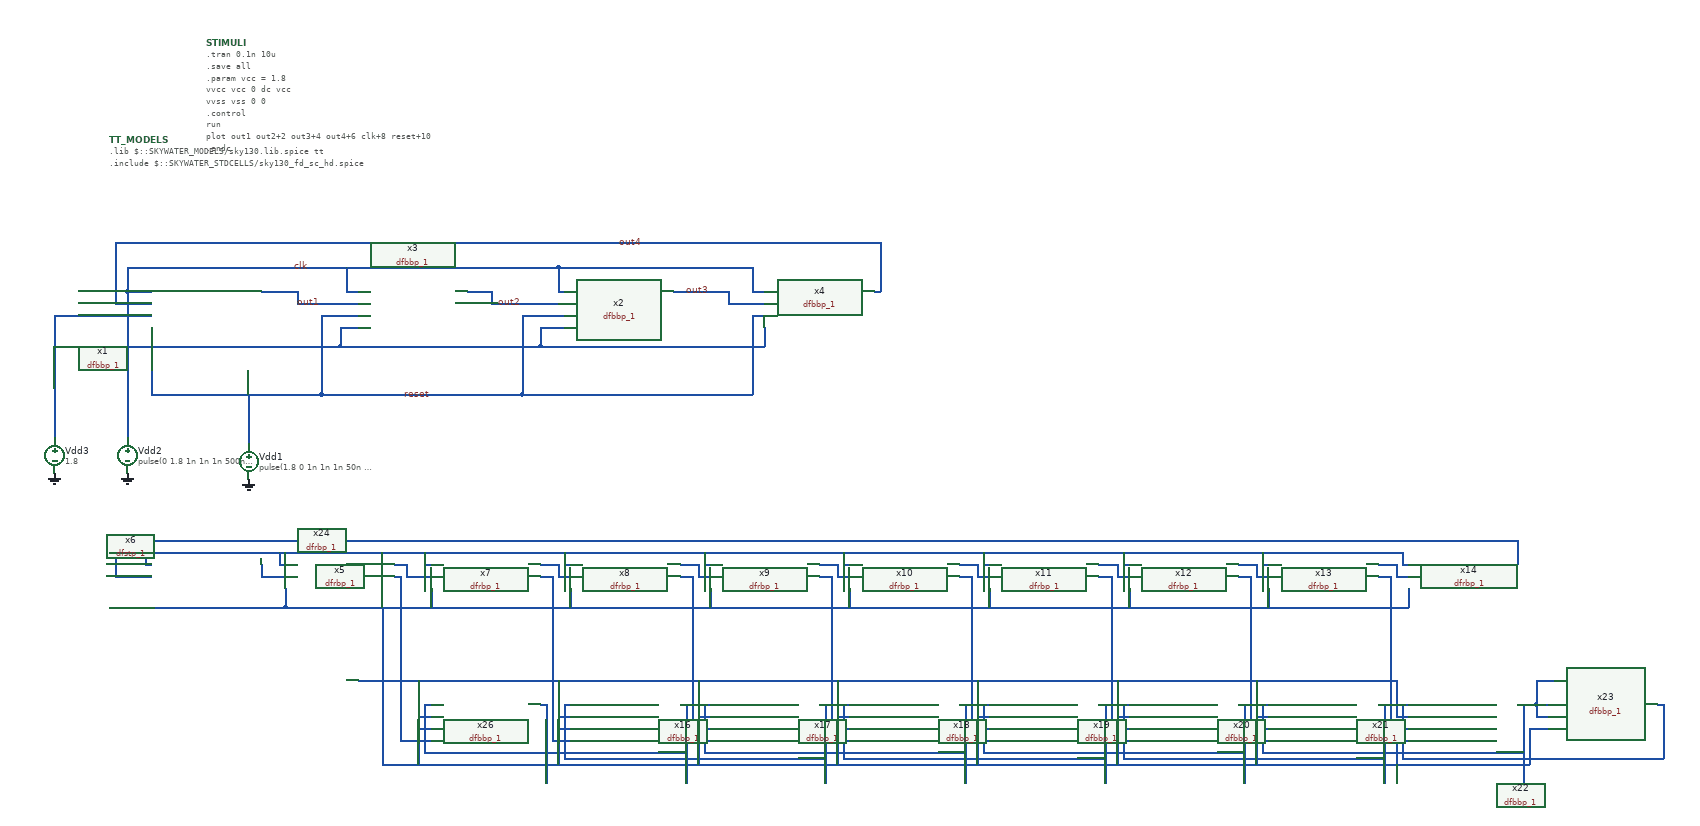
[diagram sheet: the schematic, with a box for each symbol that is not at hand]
v {xschem version=3.4.5 file_version=1.2
}
G {}
K {}
V {}
S {}
E {}
N -80 240 -80 270 {
lab=#net1}
N -80 240 80 240 {
lab=#net1}
N 260 200 320 200 {
lab=out1}
N 40 200 80 200 {
lab=clk}
N 320 200 320 220 {
lab=out1}
N 320 220 420 220 {
lab=out1}
N 600 200 640 200 {
lab=out2}
N 640 200 640 220 {
lab=out2}
N 640 220 760 220 {
lab=out2}
N 40 160 40 200 {
lab=clk}
N 60 160 750 160 {
lab=clk}
N 750 160 750 200 {
lab=clk}
N 750 200 760 200 {
lab=clk}
N 400 200 420 200 {
lab=clk}
N 400 160 400 200 {
lab=clk}
N -80 270 -80 360 {
lab=#net1}
N 390 240 420 240 {
lab=reset}
N 390 260 420 260 {
lab=#net1}
N 390 290 720 290 {
lab=#net1}
N 720 240 760 240 {
lab=reset}
N 720 260 760 260 {
lab=#net1}
N 20 120 940 120 {
lab=out4}
N 20 120 20 220 {
lab=out4}
N 40 160 60 160 {
lab=clk}
N -80 290 390 290 {
lab=#net1}
N 40 200 40 260 {
lab=clk}
N 20 220 80 220 {
lab=out4}
N 80 260 80 370 {
lab=reset}
N 650 220 750 220 {
lab=out2}
N 720 260 720 290 {
lab=#net1}
N 390 260 390 290 {
lab=#net1}
N 200 370 360 370 {
lab=reset}
N 360 240 360 370 {
lab=reset}
N 360 240 390 240 {
lab=reset}
N 360 370 690 370 {
lab=reset}
N 690 240 690 370 {
lab=reset}
N 690 240 720 240 {
lab=reset}
N 750 160 1070 160 {
lab=clk}
N 1070 160 1070 200 {
lab=clk}
N 1070 200 1090 200 {
lab=clk}
N 940 200 1030 200 {
lab=out3}
N 1030 200 1030 220 {
lab=out3}
N 1030 220 1090 220 {
lab=out3}
N 690 370 1070 370 {
lab=reset}
N 1070 240 1070 370 {
lab=reset}
N 1070 240 1090 240 {
lab=reset}
N 720 290 1090 290 {
lab=#net1}
N 1090 260 1090 290 {
lab=#net1}
N 940 120 1280 120 {
lab=out4}
N 1280 120 1280 200 {
lab=out4}
N 1270 200 1280 200 {
lab=out4}
N 40 260 40 440 {
lab=clk}
N -80 350 -80 440 {
lab=#net1}
N 80 370 200 370 {
lab=reset}
N 240 370 240 450 {
lab=reset}
N 730 880 730 1010 {
lab=#net2}
N 960 880 960 1010 {
lab=#net3}
N 1190 880 1190 1010 {
lab=#net4}
N 1420 880 1420 1010 {
lab=#net5}
N 1650 880 1650 1010 {
lab=#net6}
N 1880 880 1880 1010 {
lab=#net7}
N 2110 880 2110 1010 {
lab=#net8}
N 2340 880 2340 1010 {
lab=#net9}
N 260 650 260 670 {
lab=#net10}
N 2330 610 2330 650 {
lab=#net11}
N 20 610 2330 610 {
lab=#net11}
N 20 610 20 670 {
lab=#net11}
N 20 670 80 670 {
lab=#net11}
N 490 670 490 940 {
lab=#net12}
N 490 940 540 940 {
lab=#net12}
N 720 880 730 880 {
lab=#net2}
N 950 880 960 880 {
lab=#net3}
N 1180 880 1190 880 {
lab=#net4}
N 1410 880 1420 880 {
lab=#net5}
N 1640 880 1650 880 {
lab=#net6}
N 1870 880 1880 880 {
lab=#net7}
N 2100 880 2110 880 {
lab=#net8}
N 2330 880 2340 880 {
lab=#net9}
N 2560 880 2570 880 {
lab=#net13}
N 260 670 300 670 {
lab=#net10}
N 480 650 500 650 {
lab=#net14}
N 500 650 500 670 {
lab=#net14}
N 500 670 540 670 {
lab=#net14}
N 480 670 490 670 {
lab=#net12}
N 720 650 740 650 {
lab=#net15}
N 740 650 750 650 {
lab=#net15}
N 750 650 750 670 {
lab=#net15}
N 750 670 770 670 {
lab=#net15}
N 720 670 740 670 {
lab=#net16}
N 740 670 740 940 {
lab=#net16}
N 950 650 980 650 {
lab=#net17}
N 980 650 980 670 {
lab=#net17}
N 980 670 1000 670 {
lab=#net17}
N 950 670 970 670 {
lab=#net18}
N 970 670 970 940 {
lab=#net18}
N 970 940 1000 940 {
lab=#net18}
N 1180 650 1210 650 {
lab=#net19}
N 1210 650 1210 670 {
lab=#net19}
N 1210 670 1230 670 {
lab=#net19}
N 1180 670 1200 670 {
lab=#net20}
N 1200 670 1200 940 {
lab=#net20}
N 1200 940 1230 940 {
lab=#net20}
N 1410 650 1440 650 {
lab=#net21}
N 1440 650 1440 670 {
lab=#net21}
N 1440 670 1460 670 {
lab=#net21}
N 1410 670 1430 670 {
lab=#net22}
N 1430 670 1430 940 {
lab=#net22}
N 1430 940 1460 940 {
lab=#net22}
N 1640 650 1670 650 {
lab=#net23}
N 1670 650 1670 670 {
lab=#net23}
N 1670 670 1690 670 {
lab=#net23}
N 1640 670 1660 670 {
lab=#net24}
N 1660 670 1660 940 {
lab=#net24}
N 1660 940 1690 940 {
lab=#net24}
N 1870 650 1900 650 {
lab=#net25}
N 1900 650 1900 670 {
lab=#net25}
N 1900 670 1920 670 {
lab=#net25}
N 1870 670 1890 670 {
lab=#net26}
N 1890 670 1890 940 {
lab=#net26}
N 1890 940 1920 940 {
lab=#net26}
N 2100 650 2130 650 {
lab=#net27}
N 2130 650 2130 670 {
lab=#net27}
N 2130 670 2150 670 {
lab=#net27}
N 2100 670 2120 670 {
lab=#net28}
N 2120 670 2120 940 {
lab=#net28}
N 2120 940 2150 940 {
lab=#net28}
N 70 650 80 650 {
lab=#net29}
N 70 630 70 650 {
lab=#net29}
N 10 630 70 630 {
lab=#net29}
N 70 630 2140 630 {
lab=#net29}
N 2140 630 2140 650 {
lab=#net29}
N 2140 650 2150 650 {
lab=#net29}
N 1910 630 1910 650 {
lab=#net29}
N 1910 650 1920 650 {
lab=#net29}
N 1680 630 1680 650 {
lab=#net29}
N 1680 650 1690 650 {
lab=#net29}
N 1450 630 1450 650 {
lab=#net29}
N 1450 650 1460 650 {
lab=#net29}
N 1220 630 1220 650 {
lab=#net29}
N 1220 650 1230 650 {
lab=#net29}
N 990 630 990 650 {
lab=#net29}
N 990 650 1000 650 {
lab=#net29}
N 760 630 760 650 {
lab=#net29}
N 760 650 770 650 {
lab=#net29}
N 530 630 530 650 {
lab=#net29}
N 530 650 540 650 {
lab=#net29}
N 290 630 290 650 {
lab=#net29}
N 290 650 300 650 {
lab=#net29}
N 300 690 300 720 {
lab=#net13}
N 300 720 2150 720 {
lab=#net13}
N 2150 690 2150 720 {
lab=#net13}
N 1920 690 1920 720 {
lab=#net13}
N 1690 690 1690 720 {
lab=#net13}
N 1460 690 1460 720 {
lab=#net13}
N 1230 690 1230 720 {
lab=#net13}
N 1000 690 1000 720 {
lab=#net13}
N 770 690 770 720 {
lab=#net13}
N 540 690 540 720 {
lab=#net13}
N 420 840 2130 840 {
lab=#net30}
N 2130 840 2130 900 {
lab=#net30}
N 2130 900 2150 900 {
lab=#net30}
N 1900 900 1920 900 {
lab=#net30}
N 1900 840 1900 900 {
lab=#net30}
N 1670 900 1690 900 {
lab=#net30}
N 1670 840 1670 900 {
lab=#net30}
N 1440 900 1460 900 {
lab=#net30}
N 1440 840 1440 900 {
lab=#net30}
N 1210 900 1230 900 {
lab=#net30}
N 1210 840 1210 900 {
lab=#net30}
N 980 900 1000 900 {
lab=#net30}
N 980 840 980 900 {
lab=#net30}
N 750 900 770 900 {
lab=#net30}
N 750 840 750 900 {
lab=#net30}
N 520 900 540 900 {
lab=#net30}
N 520 840 520 900 {
lab=#net30}
N 10 720 300 720 {
lab=#net13}
N 460 720 460 970 {
lab=#net13}
N 460 980 2350 980 {
lab=#net13}
N 2350 920 2350 970 {
lab=#net13}
N 2350 920 2380 920 {
lab=#net13}
N 2130 920 2150 920 {
lab=#net13}
N 1900 920 1920 920 {
lab=#net13}
N 1670 920 1690 920 {
lab=#net13}
N 1440 920 1460 920 {
lab=#net13}
N 1210 920 1230 920 {
lab=#net13}
N 980 920 1000 920 {
lab=#net13}
N 750 920 770 920 {
lab=#net13}
N 750 920 750 970 {
lab=#net13}
N 520 920 540 920 {
lab=#net13}
N 520 920 520 970 {
lab=#net13}
N 2360 880 2380 880 {
lab=#net31}
N 2360 880 2360 900 {
lab=#net31}
N 2360 900 2380 900 {
lab=#net31}
N 2360 840 2360 880 {
lab=#net31}
N 2360 840 2390 840 {
lab=#net31}
N 530 880 540 880 {
lab=#net3}
N 760 880 770 880 {
lab=#net4}
N 740 940 770 940 {
lab=#net16}
N 990 880 990 960 {
lab=#net5}
N 990 880 1000 880 {
lab=#net5}
N 1220 880 1230 880 {
lab=#net6}
N 1450 880 1460 880 {
lab=#net7}
N 1680 880 1690 880 {
lab=#net8}
N 1910 880 1920 880 {
lab=#net9}
N 2140 880 2150 880 {
lab=#net13}
N 460 970 460 980 {
lab=#net13}
N 520 970 520 980 {
lab=#net13}
N 750 970 750 980 {
lab=#net13}
N 2350 970 2350 980 {
lab=#net13}
N 530 880 530 960 {
lab=#net3}
N 530 960 960 960 {
lab=#net3}
N 760 880 760 970 {
lab=#net4}
N 760 970 1190 970 {
lab=#net4}
N 980 920 980 980 {
lab=#net13}
N 990 960 1420 960 {
lab=#net5}
N 1210 920 1210 980 {
lab=#net13}
N 1220 880 1220 970 {
lab=#net6}
N 1220 970 1650 970 {
lab=#net6}
N 1440 920 1440 980 {
lab=#net13}
N 1450 880 1450 960 {
lab=#net7}
N 1450 960 1880 960 {
lab=#net7}
N 1670 920 1670 980 {
lab=#net13}
N 1680 880 1680 970 {
lab=#net8}
N 1680 970 2110 970 {
lab=#net8}
N 1900 920 1900 980 {
lab=#net13}
N 1910 880 1910 960 {
lab=#net9}
N 1910 960 2340 960 {
lab=#net9}
N 2130 920 2130 980 {
lab=#net13}
N 2140 880 2140 970 {
lab=#net13}
N 2140 970 2570 970 {
lab=#net13}
N 2570 880 2570 970 {
lab=#net13}
C {devices/code.sym} 10 -50 0 0 {name=TT_MODELS
only_toplevel=true
format="tcleval(@value )"
value=".lib $::SKYWATER_MODELS/sky130.lib.spice tt
.include $::SKYWATER_STDCELLS/sky130_fd_sc_hd.spice
"
spice_ignore=false
place=header}
C {devices/code_shown.sym} 170 -210 0 0 {name=STIMULI
only_toplevel=true
value="
.tran 0.1n 10u
.save all
.param vcc = 1.8
vvcc vcc 0 dc vcc
vvss vss 0 0
.control

run

plot out1 out2+2 out3+4 out4+6 clk+8 reset+10

.endc
"}
C {sky130_stdcells/dfbbp_1.sym} 170 230 0 0 {name=x1 VGND=vss VNB=vss VPB=vcc VPWR=vcc prefix=sky130_fd_sc_hd__ }
C {vsource.sym} 40 470 0 0 {name=Vdd2 value="pulse(0 1.8 1n 1n 1n 500n 1u)" savecurrent=false}
C {gnd.sym} 40 500 0 0 {name=l2 lab=GND}
C {vsource.sym} -80 470 0 0 {name=Vdd3 value=1.8 savecurrent=false}
C {gnd.sym} -80 500 0 0 {name=l3 lab=GND}
C {sky130_stdcells/dfbbp_1.sym} 510 230 0 0 {name=x3 VGND=vss VNB=vss VPB=vcc VPWR=vcc prefix=sky130_fd_sc_hd__ }
C {sky130_stdcells/dfbbp_1.sym} 850 230 0 0 {name=x2 VGND=vss VNB=vss VPB=vcc VPWR=vcc prefix=sky130_fd_sc_hd__ }
C {vsource.sym} 240 480 0 0 {name=Vdd1 value="pulse(1.8 0 1n 1n 1n 50n 100u)" savecurrent=false}
C {gnd.sym} 240 510 0 0 {name=l1 lab=GND}
C {lab_wire.sym} 360 220 0 0 {name=p1 sig_type=std_logic lab=out1}
C {lab_wire.sym} 690 220 0 0 {name=p2 sig_type=std_logic lab=out2}
C {lab_wire.sym} 890 120 0 0 {name=p3 sig_type=std_logic lab=out4}
C {lab_wire.sym} 340 160 0 0 {name=p4 sig_type=std_logic lab=clk}
C {lab_wire.sym} 540 370 0 0 {name=p5 sig_type=std_logic lab=reset}
C {sky130_stdcells/dfbbp_1.sym} 1180 230 0 0 {name=x4 VGND=vss VNB=vss VPB=vcc VPWR=vcc prefix=sky130_fd_sc_hd__ }
C {lab_wire.sym} 1000 200 0 0 {name=p6 sig_type=std_logic lab=out3}
C {sky130_stdcells/dfstp_1.sym} 170 670 0 0 {name=x6 VGND=VGND VNB=VNB VPB=VPB VPWR=VPWR prefix=sky130_fd_sc_hd__ }
C {sky130_stdcells/dfbbp_1.sym} 630 910 0 0 {name=x26 VGND=vss VNB=vss VPB=vcc VPWR=vcc prefix=sky130_fd_sc_hd__ }
C {sky130_stdcells/dfbbp_1.sym} 860 910 0 0 {name=x16 VGND=vss VNB=vss VPB=vcc VPWR=vcc prefix=sky130_fd_sc_hd__ }
C {sky130_stdcells/dfbbp_1.sym} 1090 910 0 0 {name=x17 VGND=vss VNB=vss VPB=vcc VPWR=vcc prefix=sky130_fd_sc_hd__ }
C {sky130_stdcells/dfbbp_1.sym} 1320 910 0 0 {name=x18 VGND=vss VNB=vss VPB=vcc VPWR=vcc prefix=sky130_fd_sc_hd__ }
C {sky130_stdcells/dfbbp_1.sym} 1550 910 0 0 {name=x19 VGND=vss VNB=vss VPB=vcc VPWR=vcc prefix=sky130_fd_sc_hd__ }
C {sky130_stdcells/dfbbp_1.sym} 1780 910 0 0 {name=x20 VGND=vss VNB=vss VPB=vcc VPWR=vcc prefix=sky130_fd_sc_hd__ }
C {sky130_stdcells/dfbbp_1.sym} 2010 910 0 0 {name=x21 VGND=vss VNB=vss VPB=vcc VPWR=vcc prefix=sky130_fd_sc_hd__ }
C {sky130_stdcells/dfbbp_1.sym} 2240 910 0 0 {name=x22 VGND=vss VNB=vss VPB=vcc VPWR=vcc prefix=sky130_fd_sc_hd__ }
C {sky130_stdcells/dfbbp_1.sym} 2470 910 0 0 {name=x23 VGND=vss VNB=vss VPB=vcc VPWR=vcc prefix=sky130_fd_sc_hd__ }
C {sky130_stdcells/dfrbp_1.sym} 390 670 0 0 {name=x24 VGND=VGND VNB=VNB VPB=VPB VPWR=VPWR prefix=sky130_fd_sc_hd__ }
C {sky130_stdcells/dfrbp_1.sym} 390 670 0 0 {name=x5 VGND=VGND VNB=VNB VPB=VPB VPWR=VPWR prefix=sky130_fd_sc_hd__ }
C {sky130_stdcells/dfrbp_1.sym} 630 670 0 0 {name=x7 VGND=VGND VNB=VNB VPB=VPB VPWR=VPWR prefix=sky130_fd_sc_hd__ }
C {sky130_stdcells/dfrbp_1.sym} 860 670 0 0 {name=x8 VGND=VGND VNB=VNB VPB=VPB VPWR=VPWR prefix=sky130_fd_sc_hd__ }
C {sky130_stdcells/dfrbp_1.sym} 1090 670 0 0 {name=x9 VGND=VGND VNB=VNB VPB=VPB VPWR=VPWR prefix=sky130_fd_sc_hd__ }
C {sky130_stdcells/dfrbp_1.sym} 1320 670 0 0 {name=x10 VGND=VGND VNB=VNB VPB=VPB VPWR=VPWR prefix=sky130_fd_sc_hd__ }
C {sky130_stdcells/dfrbp_1.sym} 1550 670 0 0 {name=x11 VGND=VGND VNB=VNB VPB=VPB VPWR=VPWR prefix=sky130_fd_sc_hd__ }
C {sky130_stdcells/dfrbp_1.sym} 1780 670 0 0 {name=x12 VGND=VGND VNB=VNB VPB=VPB VPWR=VPWR prefix=sky130_fd_sc_hd__ }
C {sky130_stdcells/dfrbp_1.sym} 2010 670 0 0 {name=x13 VGND=VGND VNB=VNB VPB=VPB VPWR=VPWR prefix=sky130_fd_sc_hd__ }
C {sky130_stdcells/dfrbp_1.sym} 2240 670 0 0 {name=x14 VGND=VGND VNB=VNB VPB=VPB VPWR=VPWR prefix=sky130_fd_sc_hd__ }
